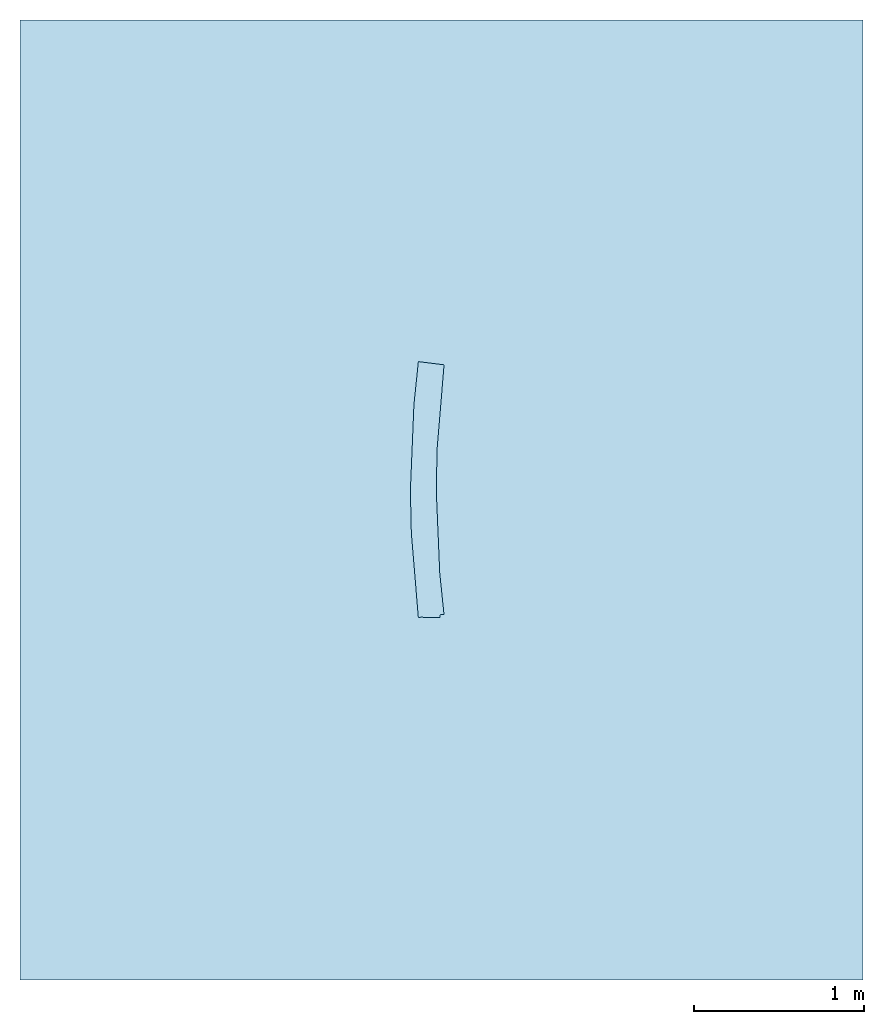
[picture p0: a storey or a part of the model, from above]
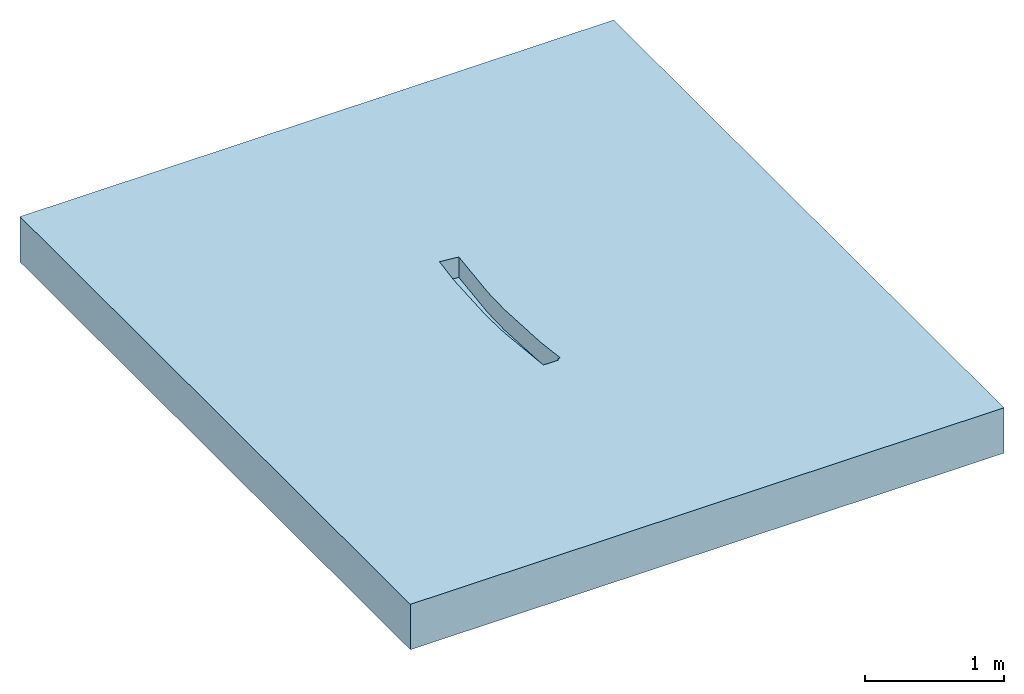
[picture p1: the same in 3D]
Properties of the parts of a building model (IFC2X3)

# File
Description: ViewDefinition [CoordinationView]
File name: 4999 - RH drop kerb.ifc
Time: 2013-09-12T12:55:23
Written by: Autodesk Revit 2013
Made in: 20120221_2030(x64)

# IfcProject, Project Number
LongName: Project Name; Phase: Project Status

# IfcSite, Default
RefLatitude: 42, 21, 30, 344238; RefLongitude: -71, -3, -35, -194702; RefElevation: 0 mm

# IfcBuilding
Pset_BuildingCommon - NumberOfStoreys: 2
Other - Project Status: Project Status; Client Name: Owner; Project Address: Enter address here; Project Issue Date: Issue Date; Project Number: Project Number; Project Name: Project Name

# IfcBuildingStorey (2)
Constraints - Elevation Base: 0
Graphics - Line Weight: 1; Symbol at End 1 Default: no; Color: 0; Symbol: M_Level Head - Circle: M_Level Head - Circle; Line Pattern: Center; Symbol at End 2 Default: yes
Dimensions - Computation Height: 0 mm
Identity Data - Building Story: yes; Structural: no
Name | LongName = Name | Elevation (mm) = Constraints, Elevation (mm)
T.O. Fnd. Wall | T.O. Fnd. Wall | -300
Level 1 | Level 1 | 0

# IfcBuildingElementProxy: 4999 - RH drop kerb, Civil-Drainage-Channel-ACO-KerbDrain-HB305 Part 2:4999 - RH drop kerb:4999 - RH drop kerb:263456
In: T.O. Fnd. Wall
Material: ACO Polymer Concrete.
General - TagNumber: 0.000000; SerialNumber: 0.000000
Materials and Finishes - Access Cover/Frame Material: N/A; Connection Pipe Material Colour: N/A; Access Cover/Frame Finish: N/A; End Cap Colour: N/A; Connection Pipe Material: N/A; End Cap Material: N/A; Channel Material: Vienite® Synthetic Resin Concrete; Access Cover/Frame Colour: N/A; Channel Colour: Grey
Phasing - Phase Created: Phase 1
Dimensions - Volume: 34242550 mm3; Curved LH Void Start: 3000 mm; 1.8m Radius Unit void End: -4805 mm; Mitre Void Start: -8095 mm; Quadrant void Start: 2600.7 mm; Curved LH Void End: 3010 mm; 6m Radius Unit Void end: -6005 mm; Flush Drainable Centre Stone Void End: -4505 mm; Curved RH Void Start: 0 mm; Straight Void Depth: 0 mm; Void_Width: 100 mm; 6m Radius unit void Start: -6000 mm; Mitre Void End: -8100 mm; Curved RH Void End: -180 mm; Staright Void Depth: -180 mm; Flush Drainable Centre Stone Void Start: -4500 mm; Quadrant void End: 2620 mm; Mite Long Side Length: 500 mm; Void L Start: -3000 mm; 1.8m Radius unit Void Start: -4800 mm; mitre small length: 487 mm; Void L End: -3010 mm; Void_Length: 25 mm
Constraints - Moves With Nearby Elements: no; Level: Level: Level 1
Pset_BuildingElementProxyCommon - Reference: 4999 - RH drop kerb
Other - Revision: 1; CreatedBy: www.aco.co.uk
Identity Data - Assembly Code: D2040; Fax: +44 (0)1462 815895; Model: ACO KerbDrain HB305; Product Code: 4999; Installation guidelines: http://www.aco.co.uk/download.php?id=120 http://www.aco.co.uk/download.php?id=120; OmniClass Title: Rainwater Removal; Address: ACO Business Park, Hitchin Road, Shefford, Bedfordshire, United Kingdom SG17 5TE; Product Page URL: http://www.aco.co.uk/product_detail.php?id=3; Cost: 0; Telephone: +44 (0)1462 816666; Maintenance guidelines: http://www.aco.co.uk/download.php?id=120; Price: POA - contact ACO; e-mail Technical: technical@aco.co.uk; URL: www.aco.co.uk; Product brochure: http://www.aco.co.uk/download.php?id=120; Assembly Description: Rain Water Drainage; OmniClass Number: 23.70.50.24; e-mail Sales: customersupport@aco.co.uk; Manufacturer: ACO Technologies plc - ACO Water Management Division; Model Description: Combined kerb and drainage system; Type Comments: ACO KerbDrain HB305 half battered right-hand drop kerb assembly 6m external radius 1500mm long
Construction - KDHB305 RH drop kerb-4999: yes; KDHB305 1.8m_radius: no; KDHB305 25-11m internal_mitre: no; KDHB305 internal_angle: no; KDHB305 6m _external_radius: no; KDHB305 7-6m external_mitre: no; LH drop kerb- 6m ext rad: no; KDHB305 10-8m_external_mitre: no; KDHB305_quadrant: no; flush drainable centre stone: no; KDHB305 25-11m external_mitre: no
Data - Channel C.S.A: 0.02 to 0.008mm²; Concrete Surround Volume - Load Class A 15 - D 400 - Grass or Asphalt Pavement: N/A; ACO Hydraulic Design Software: http://www.acodesign.co.uk; Concrete Surround Volume - Load Class A 15 - D 400 - Concrete Pavement: N/A; Drainage Slot Intake area: N/A; Hydraulic Performance: http://www.aco.co.uk/download.php?id=120; Installation - Concrete Grade: Refer to brochure; Invert Depth: 155mm; Product Weight: 77.5 Kg; Connection Pipe O.D: N/A; Drainage Slot Width: N/A; Load Class: A 15 - D 400; Product Standard: BS EN 1433:2002, CE marked, Kitemarked; Product Dimensions: 1500mm x 150mm x 180mm (LxWxH)
Green Building Properties - Channel Recycled Material Content: 20% minimum; Access Cover/Frame Recyclable: N/A; Access Cover/Frame Recycled Material Content: N/A; End Cap Recyclable: N/A; Channel Recyclable: Fully recyclable; End Cap Recycled Material Content: N/A

# IfcOpeningElement: Recess (7)
In: Level 1
Constraints - Height Offset From Level: 0 mm; Related to Mass: no; Level: Level: Level 1; Room Bounding: yes
Structural - Enable Analytical Model: no; Structural: no
Dimensions - Area: 27858925 mm2; Perimeter: 21157.2 mm; Volume: 11102785348 mm3; Thickness: 400 mm
Phasing - Phase Created: Phase 1
Analytical Properties - Roughness: 1; Absorptance: 0.1
Graphics - Coarse Scale Fill Color: 0
Construction - Function: 0; Default Thickness: 400 mm

# IfcSlab: Floor:Generic Floor - 400mm, Floor:Generic Floor - 400mm:184025
In: Level 1
PredefinedType: FLOOR; Material: Default Floor 400 mm
Constraints - Height Offset From Level: 0 mm; Related to Mass: no; Level: Level: Level 1; Room Bounding: yes
Structural - Enable Analytical Model: no; Structural: no
Dimensions - Area: 27858925 mm2; Perimeter: 21157.2 mm; Volume: 11102785348 mm3; Thickness: 400 mm
Phasing - Phase Created: Phase 1
Pset_SlabCommon - Reference: Generic Floor - 400mm; IsExternal: no; LoadBearing: yes
Analytical Properties - Roughness: 1; Absorptance: 0.1
Graphics - Coarse Scale Fill Color: 0
Construction - Function: 0; Default Thickness: 400 mm
